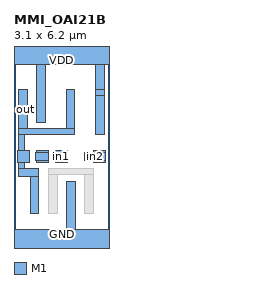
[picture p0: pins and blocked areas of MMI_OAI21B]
MACRO MMI_OAI21B
	CLASS CORE ;
	FOREIGN MMI_OAI21B 0 0 ;
	SIZE 3.1 BY 6.2 ;
	SYMMETRY X Y ;
	SITE CORE1 ;
	PIN out
		DIRECTION output ;
		USE SIGNAL ;
		PORT
			LAYER M1 ;
			RECT 0.155 3.695 0.435 4.975 ;
			LAYER M1 ;
			RECT 1.705 3.695 1.985 4.975 ;
			LAYER M1 ;
			RECT 0.155 3.505 1.985 3.695 ;
			LAYER M1 ;
			RECT 0.155 2.98 0.35 3.505 ;
			LAYER M1 ;
			RECT 0.12 2.6 0.5 2.98 ;
			LAYER M1 ;
			RECT 0.155 2.395 0.35 2.6 ;
			LAYER M1 ;
			RECT 0.155 2.13 0.815 2.395 ;
			LAYER M1 ;
			RECT 0.535 0.925 0.815 2.13 ;
		END
		AntennaDiffArea 1.8942 ;
	END out
	PIN in1
		DIRECTION input ;
		USE SIGNAL ;
		PORT
			LAYER M1 ;
			RECT 1.36 2.93 1.74 2.98 ;
			LAYER M1 ;
			RECT 1.34 2.65 1.74 2.93 ;
			LAYER M1 ;
			RECT 1.36 2.6 1.74 2.65 ;
		END
		AntennaGateArea 0.693 ;
	END in1
	PIN GND
		DIRECTION inout ;
		USE GROUND ;
		PORT
			LAYER M1 ;
			RECT 1.715 0.42 1.995 1.985 ;
			LAYER M1 ;
			RECT 0 -0.42 3.1 0.42 ;
		END
	END GND
	PIN in2
		DIRECTION input ;
		USE SIGNAL ;
		PORT
			LAYER M1 ;
			RECT 2.6 2.93 2.98 2.98 ;
			LAYER M1 ;
			RECT 2.285 2.65 2.98 2.93 ;
			LAYER M1 ;
			RECT 2.6 2.6 2.98 2.65 ;
		END
		AntennaGateArea 0.693 ;
	END in2
	PIN VDD
		DIRECTION inout ;
		USE POWER ;
		PORT
			LAYER M1 ;
			RECT 0 5.78 3.1 6.62 ;
			LAYER M1 ;
			RECT 0.745 3.915 1.025 5.78 ;
			LAYER M1 ;
			RECT 2.67 4.975 2.95 5.78 ;
			LAYER M1 ;
			RECT 2.665 4.775 2.95 4.975 ;
			LAYER M1 ;
			RECT 2.665 3.505 2.945 4.775 ;
		END
	END VDD
	PIN in0
		DIRECTION input ;
		USE SIGNAL ;
		PORT
			LAYER M1 ;
			RECT 0.74 2.93 1.12 2.98 ;
			LAYER M1 ;
			RECT 0.7 2.65 1.12 2.93 ;
			LAYER M1 ;
			RECT 0.74 2.6 1.12 2.65 ;
		END
		AntennaGateArea 0.462 ;
	END in0
	OBS
		LAYER M1 ;
		RECT 1.125 2.205 2.595 2.395 ;
		LAYER M1 ;
		RECT 1.125 0.925 1.405 2.205 ;
		LAYER M1 ;
		RECT 2.315 0.925 2.595 2.205 ;
	END
END MMI_OAI21B
